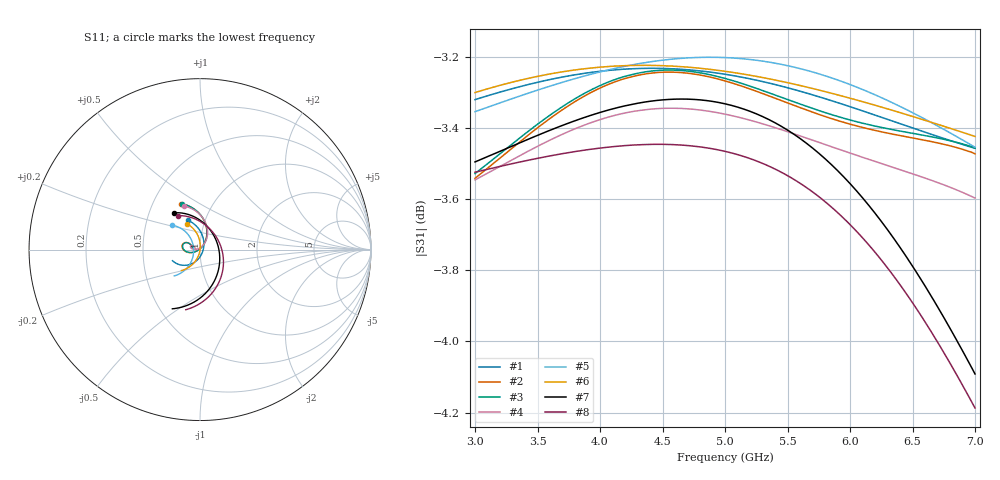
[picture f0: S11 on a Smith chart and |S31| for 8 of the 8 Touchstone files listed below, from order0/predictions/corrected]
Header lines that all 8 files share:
! |S21|, |S31| (and S12, S13) scaled, phases kept; 50 ohm, e^(+jwt)
# GHz S RI R 50
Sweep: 3 GHz to 7 GHz
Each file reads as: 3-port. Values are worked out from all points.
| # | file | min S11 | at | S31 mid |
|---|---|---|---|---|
| 1 | d1-m-nom-finer-loss-corrected.s3p | -34.7 dB | 4.825 GHz | -3.2 dB at 5 GHz |
| 2 | d2-star-sched-w-eq-em528-coarse-loss-corrected.s3p | -48.5 dB | 4.775 GHz | -3.3 dB at 5 GHz |
| 3 | d2-star-sched-w-eq-em528-finer-loss-corrected.s3p | -49.6 dB | 4.775 GHz | -3.3 dB at 5 GHz |
| 4 | d2-star-sched-w-nom-fine-loss-corrected.s3p | -40.9 dB | 5.1 GHz | -3.4 dB at 5 GHz |
| 5 | r1-m-eq-em528-loss-corrected.s3p | -28.6 dB | 5.1 GHz | -3.2 dB at 5 GHz |
| 6 | r1-m-nom-loss-corrected.s3p | -59.6 dB | 4.75 GHz | -3.2 dB at 5 GHz |
| 7 | r1t-w-eq-em528-loss-corrected.s3p | -19.4 dB | 4.825 GHz | -3.3 dB at 5 GHz |
| 8 | r1t-w-nom-loss-corrected.s3p | -18.5 dB | 4.875 GHz | -3.5 dB at 5 GHz |
